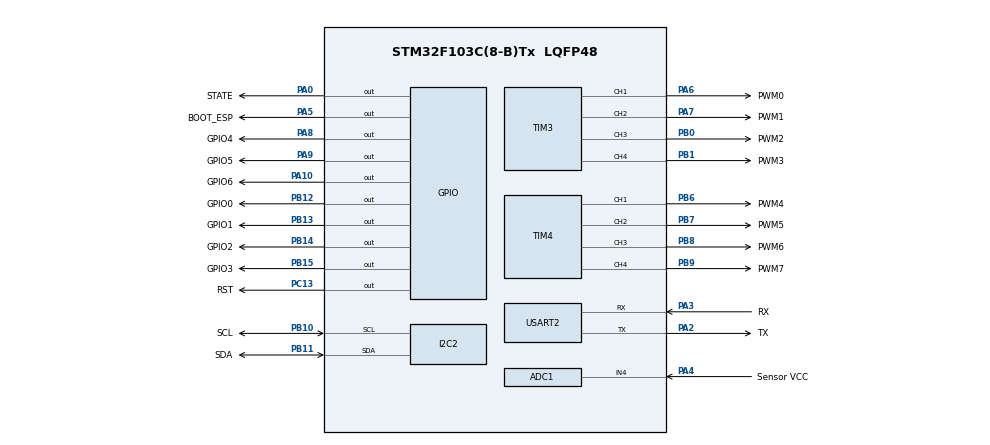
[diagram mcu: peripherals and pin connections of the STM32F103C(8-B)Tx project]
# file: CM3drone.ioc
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ADC1.Channel-0\#ChannelRegularConversion=ADC_CHANNEL_4
ADC1.ContinuousConvMode=DISABLE
ADC1.DataAlign=ADC_DATAALIGN_RIGHT
ADC1.DiscontinuousConvMode=DISABLE
ADC1.EnableAnalogWatchDog=false
ADC1.EnableRegularConversion=ENABLE
ADC1.ExternalTrigConvEdgeChoice=NONE
ADC1.InjNumberOfConversion=0
ADC1.NbrOfConversion=1
ADC1.NbrOfConversionFlag=1
ADC1.Rank-0\#ChannelRegularConversion=1
ADC1.SamplingTime-0\#ChannelRegularConversion=ADC_SAMPLETIME_1CYCLE_5
ADC1.ScanConvMode=ADC_SCAN_DISABLE
ADC1.master=1
Dma.I2C2_RX.0.Direction=DMA_PERIPH_TO_MEMORY
Dma.I2C2_RX.0.Instance=DMA1_Channel5
Dma.I2C2_RX.0.MemDataAlignment=DMA_MDATAALIGN_BYTE
Dma.I2C2_RX.0.MemInc=DMA_MINC_ENABLE
Dma.I2C2_RX.0.Mode=DMA_NORMAL
Dma.I2C2_RX.0.PeriphDataAlignment=DMA_PDATAALIGN_BYTE
Dma.I2C2_RX.0.PeriphInc=DMA_PINC_DISABLE
Dma.I2C2_RX.0.Priority=DMA_PRIORITY_VERY_HIGH
Dma.I2C2_TX.3.Direction=DMA_MEMORY_TO_PERIPH
Dma.I2C2_TX.3.Instance=DMA1_Channel4
Dma.I2C2_TX.3.MemDataAlignment=DMA_MDATAALIGN_BYTE
Dma.I2C2_TX.3.MemInc=DMA_MINC_ENABLE
Dma.I2C2_TX.3.Mode=DMA_NORMAL
Dma.I2C2_TX.3.PeriphDataAlignment=DMA_PDATAALIGN_BYTE
Dma.I2C2_TX.3.PeriphInc=DMA_PINC_DISABLE
Dma.I2C2_TX.3.Priority=DMA_PRIORITY_VERY_HIGH
Dma.Request0=I2C2_RX
Dma.Request1=USART2_RX
Dma.Request2=USART2_TX
Dma.Request3=I2C2_TX
Dma.USART2_RX.1.Direction=DMA_PERIPH_TO_MEMORY
Dma.USART2_RX.1.Instance=DMA1_Channel6
Dma.USART2_RX.1.MemDataAlignment=DMA_MDATAALIGN_BYTE
Dma.USART2_RX.1.MemInc=DMA_MINC_ENABLE
Dma.USART2_RX.1.Mode=DMA_NORMAL
Dma.USART2_RX.1.PeriphDataAlignment=DMA_PDATAALIGN_BYTE
Dma.USART2_RX.1.PeriphInc=DMA_PINC_DISABLE
Dma.USART2_RX.1.Priority=DMA_PRIORITY_HIGH
Dma.USART2_TX.2.Direction=DMA_MEMORY_TO_PERIPH
Dma.USART2_TX.2.Instance=DMA1_Channel7
Dma.USART2_TX.2.MemDataAlignment=DMA_MDATAALIGN_BYTE
Dma.USART2_TX.2.MemInc=DMA_MINC_ENABLE
Dma.USART2_TX.2.Mode=DMA_NORMAL
Dma.USART2_TX.2.PeriphDataAlignment=DMA_PDATAALIGN_BYTE
Dma.USART2_TX.2.PeriphInc=DMA_PINC_DISABLE
Dma.USART2_TX.2.Priority=DMA_PRIORITY_LOW
FREERTOS.BinarySemaphores01=CONTROL_SMPHR;IMU_SMPHR;COMPASS_SMPHR;ALTURA_SMPHR;COORDINADOR_SMPHR;AHRS_SMPHR;I2C_2_SMPHR;UART_SMPHR
FREERTOS.Mutexes01=I2C_2_MUTEX;UART_MUTEX
FREERTOS.Tasks01=defaultTask,-3,128,StartDefaultTask,Default;CONTROL_TASK,1,128,CONTROL_TASK_FCN,As external;IMU_TASK,3,128,IMU_TASK_FCN,As external;AHRS_TASK,2,128,AHRS_TASK_FCN,As external;COORDINADOR_TAS,0,128,COORDINADOR_TASK_FCN,As external;COMPASS_TASK,-1,128,COMPASS_TASK_FCN,As external;ALTURA_TASK,0,128,ALTURA_TTASK_FCN,As external
FREERTOS.Timers01=CONTROL_TIMER,CONTROL_TIMER_FCN,osTimerPeriodic,Default;IMU_TIMER,IMU_TIMER_FCN,osTimerPeriodic,Default;COORDINADOR_TIMER,COORDINADOR_TIMER_FCN,osTimerPeriodic,Default;AHRS_TIMER,AHRS_TIMER_FCN,osTimerPeriodic,Default;COMPASS_TIMER,COMPASS_TIMER_FCN,osTimerPeriodic,Default;ALTURA_TIMER,ALTURA_TIMER_FCN,osTimerPeriodic,Default
FREERTOS.configMAX_TASK_NAME_LEN=32
FREERTOS.configTIMER_TASK_PRIORITY=6
FREERTOS.configTOTAL_HEAP_SIZE=8192
FREERTOS.configUSE_TIMERS=1
I2C2.I2C_Mode=I2C_Fast
Mcu.Family=STM32F1
Mcu.Name=STM32F103C(8-B)Tx
Mcu.Package=LQFP48
NVIC.DMA1_Channel4_IRQn=true\:5\:0\:false\:false\:true\:true
NVIC.DMA1_Channel5_IRQn=true\:5\:0\:false\:false\:true\:true
NVIC.DMA1_Channel6_IRQn=true\:5\:0\:false\:false\:true\:true
NVIC.DMA1_Channel7_IRQn=true\:5\:0\:false\:false\:true\:true
NVIC.I2C2_ER_IRQn=true\:5\:0\:false\:false\:true\:true
NVIC.PriorityGroup=NVIC_PRIORITYGROUP_4
PA0-WKUP.GPIO_Label=STATE
PA0-WKUP.Signal=GPIO_Output
PA10.GPIO_Label=GPIO6
PA10.Signal=GPIO_Output
PA13.Mode=Serial_Wire
PA13.Signal=SYS_JTMS-SWDIO
PA14.Mode=Serial_Wire
PA14.Signal=SYS_JTCK-SWCLK
PA2.GPIO_Label=TX
PA2.Mode=Asynchronous
PA2.Signal=USART2_TX
PA3.GPIO_Label=RX
PA3.Mode=Asynchronous
PA3.Signal=USART2_RX
PA4.GPIO_Label=Sensor VCC
PA4.Signal=ADCx_IN4
PA5.GPIO_Label=BOOT_ESP
PA5.Signal=GPIO_Output
PA6.GPIO_Label=PWM0
PA6.Signal=S_TIM3_CH1
PA7.GPIO_Label=PWM1
PA7.Signal=S_TIM3_CH2
PA8.GPIO_Label=GPIO4
PA8.Signal=GPIO_Output
PA9.GPIO_Label=GPIO5
PA9.Signal=GPIO_Output
PB0.GPIO_Label=PWM2
PB0.Signal=S_TIM3_CH3
PB1.GPIO_Label=PWM3
PB1.Signal=S_TIM3_CH4
PB10.GPIO_Label=SCL
PB10.Mode=I2C
PB10.Signal=I2C2_SCL
PB11.GPIO_Label=SDA
PB11.Mode=I2C
PB11.Signal=I2C2_SDA
PB12.GPIO_Label=GPIO0
PB12.Signal=GPIO_Output
PB13.GPIO_Label=GPIO1
PB13.Signal=GPIO_Output
PB14.GPIO_Label=GPIO2
PB14.Signal=GPIO_Output
PB15.GPIO_Label=GPIO3
PB15.Signal=GPIO_Output
PB6.GPIO_Label=PWM4
PB6.Signal=S_TIM4_CH1
PB7.GPIO_Label=PWM5
PB7.Signal=S_TIM4_CH2
PB8.GPIO_Label=PWM6
PB8.Signal=S_TIM4_CH3
PB9.GPIO_Label=PWM7
PB9.Signal=S_TIM4_CH4
PC13-TAMPER-RTC.GPIO_Label=RST
PC13-TAMPER-RTC.Signal=GPIO_Output
ProjectManager.HeapSize=0x200
ProjectManager.StackSize=0x400
ProjectManager.TargetToolchain=MDK-ARM V5
RCC.ADCPresc=RCC_ADCPCLK2_DIV8
RCC.AHBFreq_Value=64000000
RCC.APB1CLKDivider=RCC_HCLK_DIV2
RCC.APB1Freq_Value=32000000
RCC.APB1TimFreq_Value=64000000
RCC.APB2Freq_Value=64000000
RCC.APB2TimFreq_Value=64000000
RCC.HCLKFreq_Value=64000000
RCC.HSEDivPLL=RCC_HSE_PREDIV_DIV2
RCC.HSE_VALUE=16000000
RCC.PLLMUL=RCC_PLL_MUL16
RCC.SYSCLKFreq_VALUE=64000000
RCC.SYSCLKSource=RCC_SYSCLKSOURCE_PLLCLK
RCC.USBFreq_Value=42666666.666666664
RCC.USBPrescaler=RCC_USBCLKSOURCE_PLL_DIV1_5
SH.ADCx_IN4.0=ADC1_IN4,IN4
SH.S_TIM3_CH1.0=TIM3_CH1,PWM Generation1 CH1
SH.S_TIM3_CH2.0=TIM3_CH2,PWM Generation2 CH2
SH.S_TIM3_CH3.0=TIM3_CH3,PWM Generation3 CH3
SH.S_TIM3_CH4.0=TIM3_CH4,PWM Generation4 CH4
SH.S_TIM4_CH1.0=TIM4_CH1,PWM Generation1 CH1
SH.S_TIM4_CH2.0=TIM4_CH2,PWM Generation2 CH2
SH.S_TIM4_CH3.0=TIM4_CH3,PWM Generation3 CH3
SH.S_TIM4_CH4.0=TIM4_CH4,PWM Generation4 CH4
TIM3.Channel-PWM\ Generation2\ CH2=TIM_CHANNEL_2
TIM3.Channel-PWM\ Generation3\ CH3=TIM_CHANNEL_3
TIM3.Channel-PWM\ Generation4\ CH4=TIM_CHANNEL_4
TIM4.Channel-PWM\ Generation2\ CH2=TIM_CHANNEL_2
TIM4.Channel-PWM\ Generation3\ CH3=TIM_CHANNEL_3
TIM4.Channel-PWM\ Generation4\ CH4=TIM_CHANNEL_4
VP_CRC_VS_CRC.Mode=CRC_Activate
VP_FREERTOS_VS_ENABLE.Mode=Enabled
VP_IWDG_VS_IWDG.Mode=IWDG_Activate
VP_TIM3_VS_ClockSourceINT.Mode=Internal
board=CM3drone

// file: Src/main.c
/**
  ******************************************************************************
  * File Name          : main.c
  * Description        : Main program body
  ******************************************************************************
  *
  * COPYRIGHT(c) 2016 STMicroelectronics
  *
  * Redistribution and use in source and binary forms, with or without modification,
  * are permitted provided that the following conditions are met:
  *   1. Redistributions of source code must retain the above copyright notice,
  *      this list of conditions and the following disclaimer.
  *   2. Redistributions in binary form must reproduce the above copyright notice,
  *      this list of conditions and the following disclaimer in the documentation
  *      and/or other materials provided with the distribution.
  *   3. Neither the name of STMicroelectronics nor the names of its contributors
  *      may be used to endorse or promote products derived from this software
  *      without specific prior written permission.
  *
  * THIS SOFTWARE IS PROVIDED BY THE COPYRIGHT HOLDERS AND CONTRIBUTORS "AS IS"
  * AND ANY EXPRESS OR IMPLIED WARRANTIES, INCLUDING, BUT NOT LIMITED TO, THE
  * IMPLIED WARRANTIES OF MERCHANTABILITY AND FITNESS FOR A PARTICULAR PURPOSE ARE
  * DISCLAIMED. IN NO EVENT SHALL THE COPYRIGHT HOLDER OR CONTRIBUTORS BE LIABLE
  * FOR ANY DIRECT, INDIRECT, INCIDENTAL, SPECIAL, EXEMPLARY, OR CONSEQUENTIAL
  * DAMAGES (INCLUDING, BUT NOT LIMITED TO, PROCUREMENT OF SUBSTITUTE GOODS OR
  * SERVICES; LOSS OF USE, DATA, OR PROFITS; OR BUSINESS INTERRUPTION) HOWEVER
  * CAUSED AND ON ANY THEORY OF LIABILITY, WHETHER IN CONTRACT, STRICT LIABILITY,
  * OR TORT (INCLUDING NEGLIGENCE OR OTHERWISE) ARISING IN ANY WAY OUT OF THE USE
  * OF THIS SOFTWARE, EVEN IF ADVISED OF THE POSSIBILITY OF SUCH DAMAGE.
  *
  ******************************************************************************
  */
#include "stm32f1xx_hal.h"
#include "cmsis_os.h"
#include "adc.h"
#include "crc.h"
#include "dma.h"
#include "i2c.h"
#include "iwdg.h"
#include "tim.h"
#include "usart.h"
//#include "usb_device.h"
#include "gpio.h"
#include "OSvariables.h"
#include "IMU_9DOF.h"

//CONTROL
tpEstado Estado = ESTADO_PARADA;
tpModoCalibracion ModoCalibracion;
tpModoTelemetria ModoTelemetria = TELEMETRIA_COMPLETA;
tpModoControl ModoControl = CONTROL_3EJES;
tpModoIdentificacion ModoIdentificacion;

//SENSORES
tpIMU9250 IMU9250 = {
	.Direccion_IMU = Dir_1_IMU_MPU9250,
	.Direccion_MAG = Dir_MAG_MPU9250,
	.Sensibilidad_Acel = 4,
	.Sensibilidad_Giroscopo = 2000,
	.Sensibilidad_Brujula = 19, //TODO ajustar
};

tpCalibracionIMU9DOF CalibracionIMU9DOF = {
		.Correccion_Alineamiento_IMU_matriz = {32767, 0, 0, 0, 32767, 0, 0, 0, 32767},
		.Correccion_Alineamiento_IMU = {3, 1, CalibracionIMU9DOF.Correccion_Alineamiento_IMU_matriz},
		.Correccion_COMPASS_matriz = {32767, 0, 0, 0, 32767, 0, 0, 0, 32767},
		.Correccion_COMPASS = {3, 1, CalibracionIMU9DOF.Correccion_COMPASS_matriz},
};

void SystemClock_Config(void);
void Error_Handler(void);
void MX_FREERTOS_Init(void);

int main(void)
{

  /* Reset of all peripherals, Initializes the Flash interface and the Systick. */
  HAL_Init();

  /* Configure the system clock */
  SystemClock_Config();

  /* Initialize all configured peripherals */
  MX_GPIO_Init();
  MX_DMA_Init();
  MX_ADC1_Init();
  MX_I2C2_Init();
  MX_IWDG_Init();
  MX_TIM3_Init();
  MX_TIM4_Init();
  MX_USART2_UART_Init();
  MX_CRC_Init();

  /* USER CODE BEGIN */

  /* Call init function for freertos objects (in freertos.c) */
  MX_FREERTOS_Init();

  //TODO cargar configuracion de la flash

  /* Start scheduler */
  osKernelStart();

  while (1){
  }

}

/** System Clock Configuration
*/
void SystemClock_Config(void)
{

  RCC_OscInitTypeDef RCC_OscInitStruct;
  RCC_ClkInitTypeDef RCC_ClkInitStruct;
  RCC_PeriphCLKInitTypeDef PeriphClkInit;

  RCC_OscInitStruct.OscillatorType = RCC_OSCILLATORTYPE_LSI|RCC_OSCILLATORTYPE_HSE;
  RCC_OscInitStruct.HSEState = RCC_HSE_ON;
  RCC_OscInitStruct.HSEPredivValue = RCC_HSE_PREDIV_DIV2;
  RCC_OscInitStruct.LSIState = RCC_LSI_ON;
  RCC_OscInitStruct.PLL.PLLState = RCC_PLL_ON;
  RCC_OscInitStruct.PLL.PLLSource = RCC_PLLSOURCE_HSE;
  RCC_OscInitStruct.PLL.PLLMUL = RCC_PLL_MUL9;
  if (HAL_RCC_OscConfig(&RCC_OscInitStruct) != HAL_OK)
  {
    Error_Handler();
  }

  RCC_ClkInitStruct.ClockType = RCC_CLOCKTYPE_HCLK|RCC_CLOCKTYPE_SYSCLK
                              |RCC_CLOCKTYPE_PCLK1|RCC_CLOCKTYPE_PCLK2;
  RCC_ClkInitStruct.SYSCLKSource = RCC_SYSCLKSOURCE_PLLCLK;
  RCC_ClkInitStruct.AHBCLKDivider = RCC_SYSCLK_DIV1;
  RCC_ClkInitStruct.APB1CLKDivider = RCC_HCLK_DIV2;
  RCC_ClkInitStruct.APB2CLKDivider = RCC_HCLK_DIV1;
  if (HAL_RCC_ClockConfig(&RCC_ClkInitStruct, FLASH_LATENCY_2) != HAL_OK)
  {
    Error_Handler();
  }

  PeriphClkInit.PeriphClockSelection = RCC_PERIPHCLK_ADC|RCC_PERIPHCLK_USB;
  PeriphClkInit.AdcClockSelection = RCC_ADCPCLK2_DIV6;
  PeriphClkInit.UsbClockSelection = RCC_USBCLKSOURCE_PLL_DIV1_5;
  if (HAL_RCCEx_PeriphCLKConfig(&PeriphClkInit) != HAL_OK)
  {
    Error_Handler();
  }

  HAL_SYSTICK_Config(HAL_RCC_GetHCLKFreq()/1000);

  HAL_SYSTICK_CLKSourceConfig(SYSTICK_CLKSOURCE_HCLK);

  /* SysTick_IRQn interrupt configuration */
  HAL_NVIC_SetPriority(SysTick_IRQn, 15, 0);
}

void Error_Handler(void)
{
  while(1)
  {
  }
}

extern uint16_t Sensibilidad_Giroscopo(){
	return (IMU9250.Sensibilidad_Giroscopo);
}

/************************ (C) COPYRIGHT STMicroelectronics *****END OF FILE****/

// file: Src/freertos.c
/**
  ******************************************************************************
  * File Name          : freertos.c
  * Description        : Code for freertos applications
  ******************************************************************************
  *
  * COPYRIGHT(c) 2016 STMicroelectronics
  *
  * Redistribution and use in source and binary forms, with or without modification,
  * are permitted provided that the following conditions are met:
  *   1. Redistributions of source code must retain the above copyright notice,
  *      this list of conditions and the following disclaimer.
  *   2. Redistributions in binary form must reproduce the above copyright notice,
  *      this list of conditions and the following disclaimer in the documentation
  *      and/or other materials provided with the distribution.
  *   3. Neither the name of STMicroelectronics nor the names of its contributors
  *      may be used to endorse or promote products derived from this software
  *      without specific prior written permission.
  *
  * THIS SOFTWARE IS PROVIDED BY THE COPYRIGHT HOLDERS AND CONTRIBUTORS "AS IS"
  * AND ANY EXPRESS OR IMPLIED WARRANTIES, INCLUDING, BUT NOT LIMITED TO, THE
  * IMPLIED WARRANTIES OF MERCHANTABILITY AND FITNESS FOR A PARTICULAR PURPOSE ARE
  * DISCLAIMED. IN NO EVENT SHALL THE COPYRIGHT HOLDER OR CONTRIBUTORS BE LIABLE
  * FOR ANY DIRECT, INDIRECT, INCIDENTAL, SPECIAL, EXEMPLARY, OR CONSEQUENTIAL
  * DAMAGES (INCLUDING, BUT NOT LIMITED TO, PROCUREMENT OF SUBSTITUTE GOODS OR
  * SERVICES; LOSS OF USE, DATA, OR PROFITS; OR BUSINESS INTERRUPTION) HOWEVER
  * CAUSED AND ON ANY THEORY OF LIABILITY, WHETHER IN CONTRACT, STRICT LIABILITY,
  * OR TORT (INCLUDING NEGLIGENCE OR OTHERWISE) ARISING IN ANY WAY OUT OF THE USE
  * OF THIS SOFTWARE, EVEN IF ADVISED OF THE POSSIBILITY OF SUCH DAMAGE.
  *
  ******************************************************************************
  */

#include "FreeRTOS.h"
#include "task.h"
#include "cmsis_os.h"

osThreadId defaultTaskHandle;
osThreadId CONTROL_TASKHandle;
osThreadId IMU_TASKHandle;
osThreadId AHRS_TASKHandle;
osThreadId COORDINADOR_TASHandle;
osThreadId COMPASS_TASKHandle;
osThreadId ALTURA_TASKHandle;
osTimerId CONTROL_TIMERHandle;
osTimerId IMU_TIMERHandle;
osTimerId COORDINADOR_TIMERHandle;
osTimerId AHRS_TIMERHandle;
osTimerId COMPASS_TIMERHandle;
osTimerId ALTURA_TIMERHandle;
osMutexId I2C_2_MUTEXHandle;
osMutexId UART_MUTEXHandle;
osSemaphoreId CONTROL_SMPHRHandle;
osSemaphoreId IMU_SMPHRHandle;
osSemaphoreId COMPASS_SMPHRHandle;
osSemaphoreId ALTURA_SMPHRHandle;
osSemaphoreId COORDINADOR_SMPHRHandle;
osSemaphoreId AHRS_SMPHRHandle;
osSemaphoreId I2C_2_SMPHRHandle;
osSemaphoreId UART_SMPHRHandle;

QueueHandle_t AcelLecturasCola_Handle;
QueueHandle_t VelLecturasCola_Handle;
QueueHandle_t MagLecturasCola_Handle;

void StartDefaultTask(void const * argument);
extern void CONTROL_TASK_FCN(void const * argument);
extern void IMU_TASK_FCN(void const * argument);
extern void AHRS_TASK_FCN(void const * argument);
extern void COORDINADOR_TASK_FCN(void const * argument);
extern void COMPASS_TASK_FCN(void const * argument);
extern void ALTURA_TASK_FCN(void const * argument);
extern void CONTROL_TIMER_FCN(void const * argument);
extern void IMU_TIMER_FCN(void const * argument);
extern void COORDINADOR_TIMER_FCN(void const * argument);
extern void AHRS_TIMER_FCN(void const * argument);
extern void COMPASS_TIMER_FCN(void const * argument);
extern void ALTURA_TIMER_FCN(void const * argument);

extern void MX_USB_DEVICE_Init(void);
void MX_FREERTOS_Init(void); /* (MISRA C 2004 rule 8.1) */

/* Hook prototypes */

/* Init FreeRTOS */

void MX_FREERTOS_Init(void) {

  /* Create the mutex(es) */
  /* definition and creation of I2C_2_MUTEX */
  osMutexDef(I2C_2_MUTEX);
  I2C_2_MUTEXHandle = osMutexCreate(osMutex(I2C_2_MUTEX));

  /* definition and creation of UART_MUTEX */
  osMutexDef(UART_MUTEX);
  UART_MUTEXHandle = osMutexCreate(osMutex(UART_MUTEX));

  /* Create the semaphores(s) */
  /* definition and creation of CONTROL_SMPHR */
  osSemaphoreDef(CONTROL_SMPHR);
  CONTROL_SMPHRHandle = osSemaphoreCreate(osSemaphore(CONTROL_SMPHR), 1);

  /* definition and creation of IMU_SMPHR */
  osSemaphoreDef(IMU_SMPHR);
  IMU_SMPHRHandle = osSemaphoreCreate(osSemaphore(IMU_SMPHR), 1);

  /* definition and creation of COMPASS_SMPHR */
  osSemaphoreDef(COMPASS_SMPHR);
  COMPASS_SMPHRHandle = osSemaphoreCreate(osSemaphore(COMPASS_SMPHR), 1);

  /* definition and creation of ALTURA_SMPHR */
  osSemaphoreDef(ALTURA_SMPHR);
  ALTURA_SMPHRHandle = osSemaphoreCreate(osSemaphore(ALTURA_SMPHR), 1);

  /* definition and creation of COORDINADOR_SMPHR */
  osSemaphoreDef(COORDINADOR_SMPHR);
  COORDINADOR_SMPHRHandle = osSemaphoreCreate(osSemaphore(COORDINADOR_SMPHR), 1);

  /* definition and creation of AHRS_SMPHR */
  osSemaphoreDef(AHRS_SMPHR);
  AHRS_SMPHRHandle = osSemaphoreCreate(osSemaphore(AHRS_SMPHR), 1);

  /* definition and creation of I2C_2_SMPHR */
  osSemaphoreDef(I2C_2_SMPHR);
  I2C_2_SMPHRHandle = osSemaphoreCreate(osSemaphore(I2C_2_SMPHR), 1);

  /* definition and creation of UART_SMPHR */
  osSemaphoreDef(UART_SMPHR);
  UART_SMPHRHandle = osSemaphoreCreate(osSemaphore(UART_SMPHR), 1);

  /* Create the timer(s) */
  /* definition and creation of CONTROL_TIMER */
  osTimerDef(CONTROL_TIMER, CONTROL_TIMER_FCN);
  CONTROL_TIMERHandle = osTimerCreate(osTimer(CONTROL_TIMER), osTimerPeriodic, NULL);

  /* definition and creation of IMU_TIMER */
  osTimerDef(IMU_TIMER, IMU_TIMER_FCN);
  IMU_TIMERHandle = osTimerCreate(osTimer(IMU_TIMER), osTimerPeriodic, NULL);

  /* definition and creation of COORDINADOR_TIMER */
  osTimerDef(COORDINADOR_TIMER, COORDINADOR_TIMER_FCN);
  COORDINADOR_TIMERHandle = osTimerCreate(osTimer(COORDINADOR_TIMER), osTimerPeriodic, NULL);

  /* definition and creation of AHRS_TIMER */
  osTimerDef(AHRS_TIMER, AHRS_TIMER_FCN);
  AHRS_TIMERHandle = osTimerCreate(osTimer(AHRS_TIMER), osTimerPeriodic, NULL);

  /* definition and creation of COMPASS_TIMER */
  osTimerDef(COMPASS_TIMER, COMPASS_TIMER_FCN);
  COMPASS_TIMERHandle = osTimerCreate(osTimer(COMPASS_TIMER), osTimerPeriodic, NULL);

  /* definition and creation of ALTURA_TIMER */
  osTimerDef(ALTURA_TIMER, ALTURA_TIMER_FCN);
  ALTURA_TIMERHandle = osTimerCreate(osTimer(ALTURA_TIMER), osTimerPeriodic, NULL);

  /* Create the thread(s) */
  /* definition and creation of defaultTask */
  osThreadDef(defaultTask, StartDefaultTask, osPriorityIdle, 0, 128);
  defaultTaskHandle = osThreadCreate(osThread(defaultTask), NULL);

  /* definition and creation of CONTROL_TASK */
  osThreadDef(CONTROL_TASK, CONTROL_TASK_FCN, osPriorityAboveNormal, 0, 128);
  CONTROL_TASKHandle = osThreadCreate(osThread(CONTROL_TASK), NULL);

  /* definition and creation of IMU_TASK */
  osThreadDef(IMU_TASK, IMU_TASK_FCN, osPriorityRealtime, 0, 128);
  IMU_TASKHandle = osThreadCreate(osThread(IMU_TASK), NULL);

  /* definition and creation of AHRS_TASK */
  osThreadDef(AHRS_TASK, AHRS_TASK_FCN, osPriorityHigh, 0, 128);
  AHRS_TASKHandle = osThreadCreate(osThread(AHRS_TASK), NULL);

  /* definition and creation of COORDINADOR_TAS */
  osThreadDef(COORDINADOR_TASK, COORDINADOR_TASK_FCN, osPriorityNormal, 0, 128);
  COORDINADOR_TASHandle = osThreadCreate(osThread(COORDINADOR_TASK), NULL);

  /* definition and creation of COMPASS_TASK */
  osThreadDef(COMPASS_TASK, COMPASS_TASK_FCN, osPriorityBelowNormal, 0, 128);
  COMPASS_TASKHandle = osThreadCreate(osThread(COMPASS_TASK), NULL);

  /* definition and creation of ALTURA_TASK */
  osThreadDef(ALTURA_TASK, ALTURA_TASK_FCN, osPriorityNormal, 0, 128);
  ALTURA_TASKHandle = osThreadCreate(osThread(ALTURA_TASK), NULL);

  AcelLecturasCola_Handle = xQueueCreate(1, 3*sizeof(int16_t));
  VelLecturasCola_Handle = xQueueCreate(1, 3*sizeof(int16_t));
  MagLecturasCola_Handle = xQueueCreate(1, 3*sizeof(int16_t));
}

/* StartDefaultTask function */
void StartDefaultTask(void const * argument)
{
  /* init code for USB_DEVICE */
//  MX_USB_DEVICE_Init();

  for(;;)
  {
    osDelay(1);
  }
}

/************************ (C) COPYRIGHT STMicroelectronics *****END OF FILE****/
